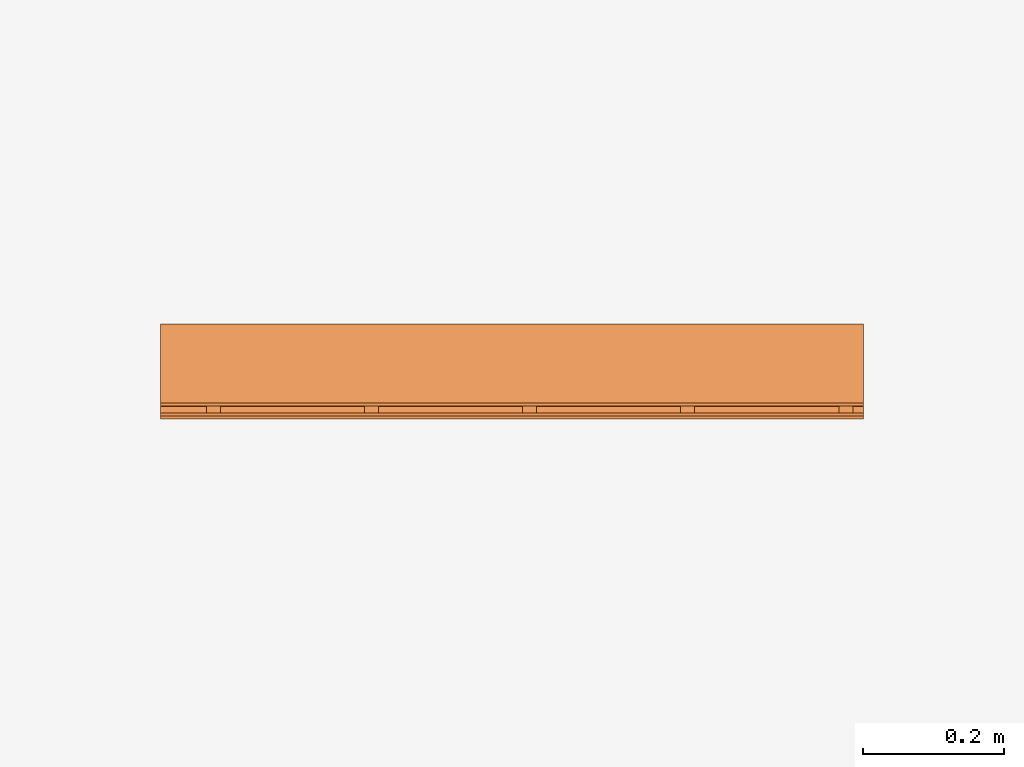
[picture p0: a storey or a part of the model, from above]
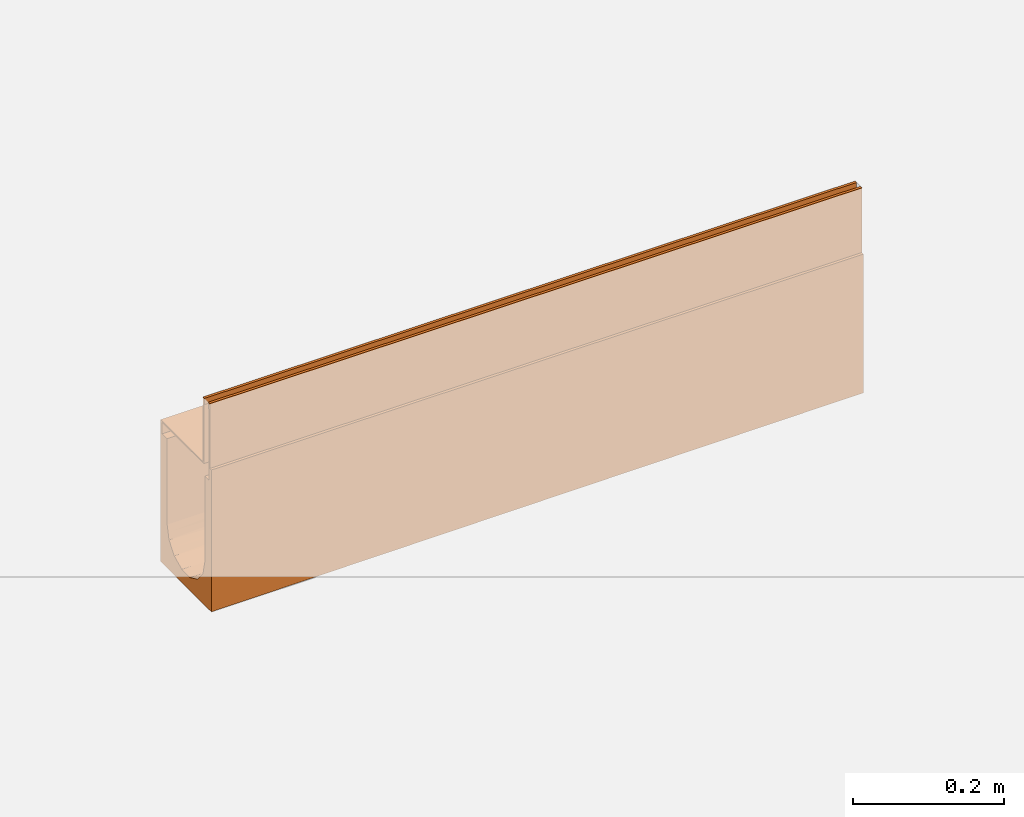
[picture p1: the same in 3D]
Properties of the parts of a building model (IFC2X3)

# File
Description: ViewDefinition [CoordinationView]
File name: 23016 - No 16 Sloping Channel - 1000mm LG - Invert Depth 205-210mm.ifc
Time: 2013-10-31T17:28:02
Written by: Autodesk Revit 2013
Made in: 20120221_2030(x64)

# IfcProject, Project Number
LongName: Project Name; Phase: Project Status

# IfcSite, Default
RefLatitude: 42, 21, 30, 344238; RefLongitude: -71, -3, -35, -194702; RefElevation: 0 mm

# IfcBuilding
Pset_BuildingCommon - NumberOfStoreys: 1
Other - Client Name: Owner; Project Issue Date: Issue Date; Project Address: ## Street City, State Zip; Project Number: Project Number; Project Status: Project Status; Project Name: Project Name

# IfcBuildingStorey, Level 1
LongName: Level 1; Elevation: 0 mm
Constraints - Elevation Base: 0; Elevation: 0 mm
Graphics - Symbol at End 1 Default: no; Line Pattern: Center; Symbol at End 2 Default: yes; Line Weight: 1; Symbol: M_Level Head - Circle: M_Level Head - Circle; Color: 0
Identity Data - Name: Level 1; Structural: no; Building Story: yes
Dimensions - Computation Height: 0 mm

# IfcBuildingElementProxy: 23016 - No 16 Sloping Channel - 1000mm LG - Invert Depth 205/210mm, Civil-Drainage-Channel-ACO-MultiDrain-M100D-Brickslot-Channel-System:23016 - No 16 Sloping Channel - 1000mm LG - Invert Depth 205/210mm:23016 - No 16 Sloping Channel - 1000mm LG - Invert Depth 205/210mm:196059
In: Level 1
Material: Steel, Galvanized, Vienite® Synthetic Resin Concrete
Construction - 23404_Universal Endcap (Female End): no; 23404_Universal Endcap (Male End): no; 23460_Load Class C250_Brickslot Grating_Galvanized Steel_1000mm Long: no; 23465_Load Class D400_Brickslot Grating_Galvanized Steel_1000mm Long: yes; 23467_Load Class D400_Brickslot Access Unit_Galvanised Steel_500mm Long: no; 23466_Load Class D400_Brickslot Grating_Galvanized Steel_500mm Long: no; 23461_Load Class C250_Brickslot Grating_Galvanized Steel_500mm Long: no; 23462_Load Class C250_Brickslot Access Unit_Galvanised Steel_500mm Long: no; Sloping Channel: yes; Constant Depth Channel: no; Shallow Depth Channel with seal: no; Constant Depth Junction Channel: no; Shallow Depth Channel: no; 23410_Sump Unit: no
Dimensions - Brickslot Void Depth: 0 mm; Brickslot Void Length: 1000 mm; EndCap Position: 1000 mm; Custom_Void_length: 0 mm; Brickslot Access Unit Void Bottom Depth: -6605 mm; Length: 1000 mm; Brickslot Access Unit Void Depth: -6500 mm; Volume: 11301178 mm3; FloorCut_Length: -1000 mm; Length Drain: -1000 mm; Brickslot Access Unit Floor Cut Length: 500 mm; GratingLength: -1000 mm; SlopingEndOverallDepth: 230 mm; SlopingEndInvertDepth: 160 mm; SlopingOverallDepth: 225 mm; Floor Cut Gap: 105 mm; FloorCut_Depth: 230 mm; Access_Custom_Void_Length: 0 mm; FloorCut_Width: 135 mm; ShallowInvDepth: 55 mm; ShallowOverallDepth: 95 mm; Depth: 150 mm; SlopingInvertDepth: 155 mm; InvDepth: 80 mm; EndCap_Height: 230 mm
Phasing - Phase Created: New Construction
Constraints - Level: Level: Level 1; Moves With Nearby Elements: no
Pset_BuildingElementProxyCommon - Reference: 23016 - No 16 Sloping Channel - 1000mm LG - Invert Depth 205/210mm
Data - Concrete Surround Volume - Load Class D 400 - Concrete Pavement: N/A; Installation - Concrete Grade: Refer to brochure; Concrete Surround Volume - Load Class B 125 - C 250 - Concrete Pavement: N/A; Load Class: A 15 - D 400; Hydraulic Performance: http://www.aco.co.uk/download.php?id=173; Product Weight: 18 Kg; Pre-formed Outlet Ø: N/A; Channel C.S.A: N/A; Product Dimensions: 1000mm x 135mm x 225mm/230mm (LxWxH); Product Standard: BS EN 1433:2002, CE marked N/A; Concrete Surround Volume - Load Class A 15 - Concrete Pavement: N/A; Invert Depth: 205mm/210mm; ACO Hydraulic Design Software: http://www.acodesign.co.uk
General - SerialNumber: 0; TagNumber: 0
Model Properties - Brickslot Grating Product code 23465: Load Class D400 - Brickslot Galvanised Steel - 1000mm long x 105mm high - 10mm Slot - Intake area - 10000mm²/m - 6.6 Kg; End Cap Product code 23404: No 306 Universal End Cap - 135mm wide x 300mm long - Spigot Ø110mm x 50mm long - Silver - Polypropylene - 0.16kg; Brickslot Grating Product code 23461: Load Class C250 - Brickslot Galvanised Steel - 500mm long x 105mm high - 10mm Slot - Intake area - 10000mm²/m -3.3 Kg; Brickslot Grating Product code 23460: Load Class C250 - Brickslot Galvanised Steel - 1000mm long x 105mm high - 10mm Slot - Intake area - 10000mm²/m - 6.6 Kg; Brickslot Access Unit Product code 23467: Load Class D400 - Brickslot Access Unit Galvanised Steel - 500mm long x 105mm high - 10mm Slot - Intake area - 10000mm²/m - 6.4 Kg; Brickslot Access Unit Product code 23462: Load Class C250 - Brickslot Access Unit Galvanised Steel - 500mm long x 105mm high - 10mm Slot - Intake area - 10000mm²/m - 6.4 Kg; Brickslot Grating Product code 23466: Load Class D400 - Brickslot Galvanised Steel - 500mm long x 105mm high - 10mm Slot - Intake area - 10000mm²/m - 3.3 Kg
Identity Data - Assembly Code: D2040; Watermark 1: This file is the property of ACO Technologies PLC; URL: www.aco.co.uk; Watermark 2: This file is water marked and users are prohibited to reproduce, adapt, distribute this information; e-mail Sales: customersupport@aco.co.uk; Assembly Description: Rain Water Drainage; Installation guidelines: http://www.aco.co.uk/download.php?id=173; Product brochure: http://www.aco.co.uk/download.php?id=173; Telephone: +44 (0)1462 816666; e-mail Technical: technical@aco.co.uk; Cost: 0; Watermarked With: BIM Manager Premium Suite; Fax: +44 (0)1462 815895; OmniClass Title: Rainwater Removal; Product Page URL: http://www.aco.co.uk/product_detail.php?id=58; Model Description: Channel drainage system; Model: ACO MultiDrain MD Brickslot- M100D; Maintenance guidelines: http://www.aco.co.uk/download.php?id=173; Price: POA - contact ACO; Manufacturer: ACO Technologies plc - ACO Water Management Division; OmniClass Number: 23.70.50.24; Type Comments: ACO MultiDrain M100D No 16 Sloping Channel 1000mm Long; Address: ACO Business Park, Hitchin Road, Shefford, Bedfordshire, United Kingdom SG17 5TE; Product Code: 23016
Green Building Properties - Channel Recycled Material Content: 20% minimum; Edge Rail Recyclable: Fully recyclable; Edge Rail Recycled Material Content: Between 40% - 90%; Channel Recyclable: Fully recyclable
Materials and Finishes - Channel Material: Vienite® Synthetic Resin Concrete; Edge Rail Finish: Pre-galvanised; Edge Rail Material: Steel; Channel Colour: Brown; Edge Rail Colour: Silver
Other - Revision: 1; Created By: www.aco.co.uk; Watermarked By: www.aco.co.uk

# IfcOpeningElement: Recess (2)
In: Level 1
Structural - Enable Analytical Model: no; Structural: no
Phasing - Phase Created: New Construction
Constraints - Level: Level: Level 1; Related to Mass: no; Height Offset From Level: 0 mm; Room Bounding: yes
Dimensions - Thickness: 1000 mm; Area: 25000000 mm2; Volume: 24967060000 mm3; Perimeter: 20000 mm
Graphics - Coarse Scale Fill Color: 0
Analytical Properties - Absorptance: 0.1; Thermal mass: 1359800; Roughness: 1; Heat Transfer Coefficient (U): 0.837; Thermal Resistance (R): 1.19474
Materials and Finishes - Structural Material: Earth
Construction - Default Thickness: 1000 mm; Function: 0

# IfcSlab: Floor:Generic Floor - 1000mm, Floor:Generic Floor - 1000mm:193825
In: Level 1
PredefinedType: FLOOR; Material: Earth 1000 mm
Structural - Enable Analytical Model: no; Structural: no
Phasing - Phase Created: New Construction
Constraints - Level: Level: Level 1; Related to Mass: no; Height Offset From Level: 0 mm; Room Bounding: yes
Dimensions - Thickness: 1000 mm; Area: 25000000 mm2; Volume: 24967060000 mm3; Perimeter: 20000 mm
Pset_SlabCommon - Reference: Generic Floor - 1000mm; IsExternal: no; LoadBearing: yes
Graphics - Coarse Scale Fill Color: 0
Analytical Properties - Absorptance: 0.1; Thermal mass: 1359800; Roughness: 1; Heat Transfer Coefficient (U): 0.837; Thermal Resistance (R): 1.19474
Materials and Finishes - Structural Material: Earth
Construction - Default Thickness: 1000 mm; Function: 0
